# FeCIM Bit Cell - Stub LEF for OpenLane Integration
# This is a PLACEHOLDER cell for simulation and array-level exploration.
# No physical implementation exists - technology is at TRL 4.
#
# Cell Dimensions: 0.46um x 2.72um (SKY130 compatible)
# Usage: Array placement in FeCIM crossbar lattice generator

VERSION 5.8 ;
BUSBITCHARS "[]" ;
DIVIDERCHAR "/" ;

SITE fecim_site
  CLASS CORE ;
  SIZE 0.46 BY 2.72 ;
  SYMMETRY X Y ;
END fecim_site

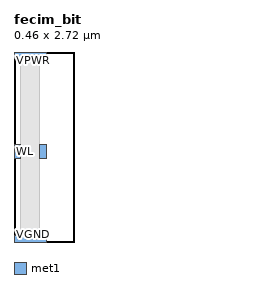
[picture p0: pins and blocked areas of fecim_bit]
MACRO fecim_bit
  CLASS CORE ;
  FOREIGN fecim_bit 0 0 ;
  ORIGIN 0 0 ;
  SIZE 0.46 BY 2.72 ;
  SYMMETRY X Y ;
  SITE fecim_site ;

  PIN WL
    DIRECTION INPUT ;
    USE SIGNAL ;
    PORT
      LAYER met1 ;
        RECT 0.000 1.200 0.100 1.400 ;
    END
  END WL

  PIN BL
    DIRECTION INOUT ;
    USE SIGNAL ;
    PORT
      LAYER met1 ;
        RECT 0.360 1.200 0.460 1.400 ;
    END
  END BL

  PIN VPWR
    DIRECTION INOUT ;
    USE POWER ;
    PORT
      LAYER met1 ;
        RECT 0.000 2.620 0.460 2.720 ;
    END
  END VPWR

  PIN VGND
    DIRECTION INOUT ;
    USE GROUND ;
    PORT
      LAYER met1 ;
        RECT 0.000 0.000 0.460 0.100 ;
    END
  END VGND

  OBS
    LAYER met1 ;
      RECT 0.100 0.100 0.360 2.620 ;
  END

END fecim_bit

END LIBRARY
